VERSION 5.8 ;
BUSBITCHARS "[]" ;
DIVIDERCHAR "/" ;
UNITS
    DATABASE MICRONS 1000 ;
END UNITS

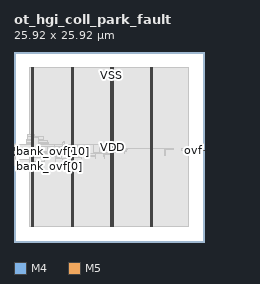
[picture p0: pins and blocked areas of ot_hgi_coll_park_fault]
MACRO ot_hgi_coll_park_fault
  FOREIGN ot_hgi_coll_park_fault 0 0 ;
  CLASS BLOCK ;
  SIZE 25.92 BY 25.92 ;
  PIN bank_ovf[0]
    DIRECTION INPUT ;
    USE SIGNAL ;
    PORT
      LAYER M4 ;
        RECT  0 11.376 0.084 11.4 ;
    END
  END bank_ovf[0]
  PIN bank_ovf[10]
    DIRECTION INPUT ;
    USE SIGNAL ;
    PORT
      LAYER M4 ;
        RECT  0 12.336 0.084 12.36 ;
    END
  END bank_ovf[10]
  PIN bank_ovf[11]
    DIRECTION INPUT ;
    USE SIGNAL ;
    PORT
      LAYER M4 ;
        RECT  0 12.432 0.084 12.456 ;
    END
  END bank_ovf[11]
  PIN bank_ovf[12]
    DIRECTION INPUT ;
    USE SIGNAL ;
    PORT
      LAYER M4 ;
        RECT  0 12.528 0.084 12.552 ;
    END
  END bank_ovf[12]
  PIN bank_ovf[13]
    DIRECTION INPUT ;
    USE SIGNAL ;
    PORT
      LAYER M4 ;
        RECT  0 12.624 0.084 12.648 ;
    END
  END bank_ovf[13]
  PIN bank_ovf[14]
    DIRECTION INPUT ;
    USE SIGNAL ;
    PORT
      LAYER M4 ;
        RECT  0 12.72 0.084 12.744 ;
    END
  END bank_ovf[14]
  PIN bank_ovf[15]
    DIRECTION INPUT ;
    USE SIGNAL ;
    PORT
      LAYER M4 ;
        RECT  0 12.816 0.084 12.84 ;
    END
  END bank_ovf[15]
  PIN bank_ovf[1]
    DIRECTION INPUT ;
    USE SIGNAL ;
    PORT
      LAYER M4 ;
        RECT  0 11.472 0.084 11.496 ;
    END
  END bank_ovf[1]
  PIN bank_ovf[2]
    DIRECTION INPUT ;
    USE SIGNAL ;
    PORT
      LAYER M4 ;
        RECT  0 11.568 0.084 11.592 ;
    END
  END bank_ovf[2]
  PIN bank_ovf[3]
    DIRECTION INPUT ;
    USE SIGNAL ;
    PORT
      LAYER M4 ;
        RECT  0 11.664 0.084 11.688 ;
    END
  END bank_ovf[3]
  PIN bank_ovf[4]
    DIRECTION INPUT ;
    USE SIGNAL ;
    PORT
      LAYER M4 ;
        RECT  0 11.76 0.084 11.784 ;
    END
  END bank_ovf[4]
  PIN bank_ovf[5]
    DIRECTION INPUT ;
    USE SIGNAL ;
    PORT
      LAYER M4 ;
        RECT  0 11.856 0.084 11.88 ;
    END
  END bank_ovf[5]
  PIN bank_ovf[6]
    DIRECTION INPUT ;
    USE SIGNAL ;
    PORT
      LAYER M4 ;
        RECT  0 11.952 0.084 11.976 ;
    END
  END bank_ovf[6]
  PIN bank_ovf[7]
    DIRECTION INPUT ;
    USE SIGNAL ;
    PORT
      LAYER M4 ;
        RECT  0 12.048 0.084 12.072 ;
    END
  END bank_ovf[7]
  PIN bank_ovf[8]
    DIRECTION INPUT ;
    USE SIGNAL ;
    PORT
      LAYER M4 ;
        RECT  0 12.144 0.084 12.168 ;
    END
  END bank_ovf[8]
  PIN bank_ovf[9]
    DIRECTION INPUT ;
    USE SIGNAL ;
    PORT
      LAYER M4 ;
        RECT  0 12.24 0.084 12.264 ;
    END
  END bank_ovf[9]
  PIN clk
    DIRECTION INPUT ;
    USE SIGNAL ;
    PORT
      LAYER M4 ;
        RECT  0 12.912 0.084 12.936 ;
    END
  END clk
  PIN ovf
    DIRECTION OUTPUT ;
    USE SIGNAL ;
    PORT
      LAYER M4 ;
        RECT  25.836 12.432 25.92 12.456 ;
    END
    PORT
      LAYER M4 ;
        RECT  24.505 12.432 25.884 12.456 ;
    END
  END ovf
  PIN rst_n
    DIRECTION INPUT ;
    USE SIGNAL ;
    PORT
      LAYER M4 ;
        RECT  0 13.008 0.084 13.032 ;
    END
  END rst_n
  PIN VDD
    DIRECTION INOUT ;
    USE POWER ;
    PORT
      LAYER M5 ;
        RECT  18.792 2.151 18.912 23.769 ;
        RECT  13.392 2.151 13.512 23.769 ;
        RECT  7.992 2.151 8.112 23.769 ;
        RECT  2.592 2.151 2.712 23.769 ;
    END
  END VDD
  PIN VSS
    DIRECTION INOUT ;
    USE GROUND ;
    PORT
      LAYER M5 ;
        RECT  18.6 2.137 18.72 23.783 ;
        RECT  13.2 2.137 13.32 23.783 ;
        RECT  7.8 2.137 7.92 23.783 ;
        RECT  2.4 2.137 2.52 23.783 ;
    END
  END VSS
  # OT_OBS_CLOSED layer=M5 d_um=1.536 added=1
  OBS
    LAYER RVTN ;
     RECT  2.16 2.16 23.76 2.295 ;
     RECT  2.16 2.565 23.76 2.835 ;
     RECT  2.16 3.105 23.76 3.375 ;
     RECT  2.16 3.645 23.76 3.915 ;
     RECT  2.16 4.185 23.76 4.455 ;
     RECT  2.16 4.725 23.76 4.995 ;
     RECT  2.16 5.265 23.76 5.535 ;
     RECT  2.16 5.805 23.76 6.075 ;
     RECT  2.16 6.345 23.76 6.615 ;
     RECT  2.16 6.885 23.76 7.155 ;
     RECT  2.16 7.425 23.76 7.695 ;
     RECT  2.16 7.965 23.76 8.235 ;
     RECT  2.16 8.505 23.76 8.775 ;
     RECT  2.16 9.045 23.76 9.315 ;
     RECT  2.16 9.585 23.76 9.855 ;
     RECT  2.16 10.125 23.76 10.395 ;
     RECT  2.16 10.665 23.76 10.935 ;
     RECT  2.16 11.205 23.76 11.475 ;
     RECT  2.16 11.745 23.76 12.015 ;
     RECT  2.16 12.285 23.76 12.555 ;
     RECT  2.16 12.825 23.76 13.095 ;
     RECT  2.16 13.365 23.76 13.635 ;
     RECT  2.16 13.905 23.76 14.175 ;
     RECT  2.16 14.445 23.76 14.715 ;
     RECT  2.16 14.985 23.76 15.255 ;
     RECT  2.16 15.525 23.76 15.795 ;
     RECT  2.16 16.065 23.76 16.335 ;
     RECT  2.16 16.605 23.76 16.875 ;
     RECT  2.16 17.145 23.76 17.415 ;
     RECT  2.16 17.685 23.76 17.955 ;
     RECT  2.16 18.225 23.76 18.495 ;
     RECT  2.16 18.765 23.76 19.035 ;
     RECT  2.16 19.305 23.76 19.575 ;
     RECT  2.16 19.845 23.76 20.115 ;
     RECT  2.16 20.385 23.76 20.655 ;
     RECT  2.16 20.925 23.76 21.195 ;
     RECT  2.16 21.465 23.76 21.735 ;
     RECT  2.16 22.005 23.76 22.275 ;
     RECT  2.16 22.545 23.76 22.815 ;
     RECT  2.16 23.085 23.76 23.355 ;
     RECT  2.16 23.625 23.76 23.76 ;
    LAYER RVTP ;
     RECT  2.16 2.295 23.76 2.565 ;
     RECT  2.16 2.835 23.76 3.105 ;
     RECT  2.16 3.375 23.76 3.645 ;
     RECT  2.16 3.915 23.76 4.185 ;
     RECT  2.16 4.455 23.76 4.725 ;
     RECT  2.16 4.995 23.76 5.265 ;
     RECT  2.16 5.535 23.76 5.805 ;
     RECT  2.16 6.075 23.76 6.345 ;
     RECT  2.16 6.615 23.76 6.885 ;
     RECT  2.16 7.155 23.76 7.425 ;
     RECT  2.16 7.695 23.76 7.965 ;
     RECT  2.16 8.235 23.76 8.505 ;
     RECT  2.16 8.775 23.76 9.045 ;
     RECT  2.16 9.315 23.76 9.585 ;
     RECT  2.16 9.855 23.76 10.125 ;
     RECT  2.16 10.395 23.76 10.665 ;
     RECT  2.16 10.935 23.76 11.205 ;
     RECT  2.16 11.475 23.76 11.745 ;
     RECT  2.16 12.015 23.76 12.285 ;
     RECT  2.16 12.555 23.76 12.825 ;
     RECT  2.16 13.095 23.76 13.365 ;
     RECT  2.16 13.635 23.76 13.905 ;
     RECT  2.16 14.175 23.76 14.445 ;
     RECT  2.16 14.715 23.76 14.985 ;
     RECT  2.16 15.255 23.76 15.525 ;
     RECT  2.16 15.795 23.76 16.065 ;
     RECT  2.16 16.335 23.76 16.605 ;
     RECT  2.16 16.875 23.76 17.145 ;
     RECT  2.16 17.415 23.76 17.685 ;
     RECT  2.16 17.955 23.76 18.225 ;
     RECT  2.16 18.495 23.76 18.765 ;
     RECT  2.16 19.035 23.76 19.305 ;
     RECT  2.16 19.575 23.76 19.845 ;
     RECT  2.16 20.115 23.76 20.385 ;
     RECT  2.16 20.655 23.76 20.925 ;
     RECT  2.16 21.195 23.76 21.465 ;
     RECT  2.16 21.735 23.76 22.005 ;
     RECT  2.16 22.275 23.76 22.545 ;
     RECT  2.16 22.815 23.76 23.085 ;
     RECT  2.16 23.355 23.76 23.625 ;
    LAYER M1 ;
     RECT  2.16 2.151 23.76 23.769 ;
    LAYER M2 ;
     RECT  0.103 10.44 0.139 10.458 ;
     RECT  0.139 10.44 0.175 10.728 ;
     RECT  1.723 13.41 1.759 13.428 ;
     RECT  1.759 13.41 1.795 13.932 ;
     RECT  0.175 10.44 2.16 11.268 ;
     RECT  0.103 12.492 2.16 12.51 ;
     RECT  1.795 13.41 2.16 14.67 ;
     RECT  2.16 2.151 23.76 23.769 ;
     RECT  23.76 12.366 24.539 12.384 ;
    LAYER M3 ;
     RECT  2.415 2.143 2.505 2.413 ;
     RECT  7.815 2.143 7.905 2.413 ;
     RECT  13.215 2.143 13.305 2.413 ;
     RECT  18.615 2.143 18.705 2.413 ;
     RECT  0.108 10.435 0.126 10.633 ;
     RECT  2.415 2.413 2.697 10.741 ;
     RECT  3.456 10.471 3.474 10.741 ;
     RECT  0.108 10.633 0.234 10.975 ;
     RECT  2.415 10.741 3.474 11.011 ;
     RECT  5.688 10.741 5.706 11.371 ;
     RECT  6.552 11.281 6.57 11.371 ;
     RECT  0.108 10.975 0.27 11.405 ;
     RECT  7.815 2.413 8.097 11.407 ;
     RECT  7.776 11.407 8.097 11.419 ;
     RECT  2.415 11.011 4.158 11.479 ;
     RECT  7.344 11.419 8.097 11.479 ;
     RECT  9.144 11.371 9.162 11.479 ;
     RECT  0.144 11.405 0.27 11.501 ;
     RECT  5.688 11.371 6.57 11.515 ;
     RECT  7.344 11.479 9.162 11.515 ;
     RECT  5.688 11.515 9.162 11.551 ;
     RECT  0.18 11.501 0.27 11.597 ;
     RECT  9.936 11.551 9.954 11.641 ;
     RECT  0.216 11.597 0.27 11.693 ;
     RECT  2.415 11.479 4.77 11.707 ;
     RECT  2.415 11.707 4.842 11.713 ;
     RECT  5.616 11.551 9.162 11.713 ;
     RECT  9.936 11.641 10.314 11.713 ;
     RECT  11.052 11.443 11.07 11.713 ;
     RECT  12.384 11.407 12.402 11.713 ;
     RECT  2.415 11.713 9.162 11.749 ;
     RECT  9.936 11.713 11.07 11.749 ;
     RECT  0.252 11.693 0.27 11.789 ;
     RECT  2.415 11.749 11.07 11.851 ;
     RECT  12.168 11.713 12.402 11.947 ;
     RECT  13.215 2.413 13.497 11.947 ;
     RECT  2.304 11.851 11.07 12.019 ;
     RECT  12.168 11.947 13.497 12.019 ;
     RECT  2.304 12.019 13.626 12.209 ;
     RECT  10.476 12.209 13.626 12.235 ;
     RECT  2.304 12.209 9.666 12.245 ;
     RECT  5.4 12.245 9.666 12.281 ;
     RECT  15.12 12.091 15.138 12.325 ;
     RECT  2.304 12.245 4.626 12.331 ;
     RECT  14.652 12.325 15.138 12.361 ;
     RECT  23.364 12.325 23.382 12.451 ;
     RECT  24.516 12.361 24.534 12.461 ;
     RECT  22.86 12.451 23.382 12.479 ;
     RECT  0.108 12.487 0.126 12.557 ;
     RECT  10.476 12.235 13.806 12.559 ;
     RECT  14.652 12.361 15.39 12.559 ;
     RECT  20.592 11.785 20.61 12.559 ;
     RECT  10.476 12.559 15.39 12.631 ;
     RECT  20.592 12.559 21.006 12.631 ;
     RECT  5.58 12.281 9.666 12.749 ;
     RECT  10.476 12.631 15.462 12.749 ;
     RECT  20.592 12.631 21.726 12.749 ;
     RECT  22.86 12.479 23.202 12.749 ;
     RECT  20.592 12.749 21.402 12.757 ;
     RECT  10.584 12.749 15.462 12.785 ;
     RECT  20.448 12.757 21.402 12.785 ;
     RECT  22.86 12.749 22.878 12.785 ;
     RECT  14.4 12.785 15.462 12.797 ;
     RECT  20.448 12.785 21.006 12.797 ;
     RECT  10.584 12.785 13.497 12.821 ;
     RECT  20.988 12.797 21.006 12.821 ;
     RECT  5.58 12.749 8.19 12.857 ;
     RECT  8.964 12.749 9.666 12.857 ;
     RECT  14.4 12.797 14.922 12.893 ;
     RECT  14.4 12.893 14.418 12.929 ;
     RECT  5.58 12.857 6.858 13.019 ;
     RECT  1.728 12.331 4.626 13.063 ;
     RECT  9.648 12.857 9.666 13.085 ;
     RECT  6.336 13.019 6.858 13.091 ;
     RECT  10.656 12.821 13.497 13.091 ;
     RECT  11.376 13.091 13.497 13.127 ;
     RECT  7.815 12.857 8.19 13.163 ;
     RECT  11.376 13.127 12.258 13.163 ;
     RECT  1.728 13.063 5.49 13.289 ;
     RECT  11.664 13.163 11.898 13.289 ;
     RECT  13.068 13.127 13.497 13.289 ;
     RECT  1.728 13.289 5.058 13.325 ;
     RECT  1.728 13.325 4.734 13.433 ;
     RECT  11.664 13.289 11.682 13.433 ;
     RECT  6.552 13.091 6.822 13.559 ;
     RECT  1.764 13.433 4.734 13.631 ;
     RECT  6.804 13.559 6.822 13.667 ;
     RECT  1.764 13.631 4.59 13.829 ;
     RECT  1.764 13.829 4.41 13.865 ;
     RECT  1.764 13.865 4.014 13.937 ;
     RECT  1.8 13.937 4.014 14.369 ;
     RECT  1.8 14.369 3.546 14.405 ;
     RECT  1.8 14.405 3.366 14.441 ;
     RECT  1.8 14.441 2.754 14.639 ;
     RECT  1.8 14.639 2.697 14.675 ;
     RECT  2.415 14.675 2.697 23.507 ;
     RECT  7.815 13.163 8.097 23.507 ;
     RECT  13.215 13.289 13.497 23.507 ;
     RECT  18.615 2.413 18.897 23.507 ;
     RECT  2.415 23.507 2.505 23.777 ;
     RECT  7.815 23.507 7.905 23.777 ;
     RECT  13.215 23.507 13.305 23.777 ;
     RECT  18.615 23.507 18.705 23.777 ;
    LAYER M4 ;
     RECT  0.06 11.376 0.133 13.032 ;
     RECT  0.133 11.376 0.137 13.368 ;
     RECT  0.137 11.472 0.173 13.368 ;
     RECT  0.173 11.568 0.209 13.368 ;
     RECT  0.209 11.664 0.245 13.368 ;
     RECT  0.245 11.76 0.281 13.368 ;
     RECT  0.281 11.856 2.408 13.368 ;
     RECT  2.408 2.148 2.512 23.772 ;
     RECT  2.512 2.418 2.704 23.502 ;
     RECT  2.704 11.712 2.981 14.28 ;
     RECT  2.981 12.864 3.299 14.28 ;
     RECT  3.299 12.864 3.341 13.368 ;
     RECT  3.341 13.248 4.241 13.368 ;
     RECT  2.981 11.712 4.853 11.736 ;
     RECT  5.389 11.904 5.641 12.024 ;
     RECT  5.641 11.904 6.181 12.072 ;
     RECT  6.181 11.424 6.437 12.072 ;
     RECT  6.437 11.424 7.808 11.976 ;
     RECT  4.241 13.344 7.808 13.368 ;
     RECT  7.808 2.148 7.912 23.772 ;
     RECT  7.912 2.418 8.104 23.502 ;
     RECT  8.104 12.048 8.633 13.368 ;
     RECT  8.633 12.096 10.865 13.368 ;
     RECT  10.865 12.24 11.693 13.368 ;
     RECT  11.693 12.24 11.939 13.272 ;
     RECT  11.939 12.24 13.208 12.504 ;
     RECT  13.208 2.148 13.312 23.772 ;
     RECT  13.312 2.418 13.504 23.502 ;
     RECT  13.504 12.24 13.817 12.6 ;
     RECT  13.817 12.384 15.185 12.6 ;
     RECT  15.185 12.48 15.293 12.6 ;
     RECT  15.433 12.768 18.608 12.792 ;
     RECT  18.608 2.148 18.712 23.772 ;
     RECT  18.712 2.418 18.904 23.502 ;
     RECT  18.904 12.768 20.477 12.792 ;
    LAYER M5 ;
     RECT  2.4 2.137 2.52 2.151 ;
     RECT  7.8 2.137 7.92 2.151 ;
     RECT  13.2 2.137 13.32 2.151 ;
     RECT  18.6 2.137 18.72 2.151 ;
     RECT  2.4 2.151 2.712 12.853 ;
     RECT  11.904 12.469 11.928 13.283 ;
     RECT  0.144 12.901 0.168 13.379 ;
     RECT  2.4 12.853 3.288 14.291 ;
     RECT  2.4 14.291 2.712 23.769 ;
     RECT  7.8 2.151 8.112 23.769 ;
     RECT  13.2 2.151 13.512 23.769 ;
     RECT  18.6 2.151 18.912 23.769 ;
     RECT  2.4 23.769 2.52 23.783 ;
     RECT  7.8 23.769 7.92 23.783 ;
     RECT  13.2 23.769 13.32 23.783 ;
     RECT  18.6 23.769 18.72 23.783 ;
     RECT  11.928 12.469 13.2 13.283 ;
  END
END ot_hgi_coll_park_fault
END LIBRARY
